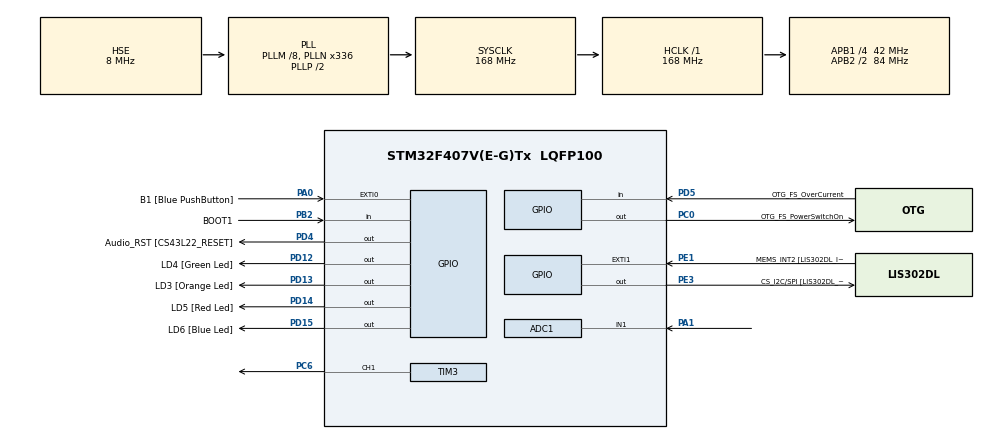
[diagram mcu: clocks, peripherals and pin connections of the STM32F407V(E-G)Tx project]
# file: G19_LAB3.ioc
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ADC1.Channel-0\#ChannelRegularConversion=ADC_CHANNEL_1
ADC1.ExternalTrigConv=ADC_EXTERNALTRIGCONV_T2_TRGO
ADC1.NbrOfConversion=1
ADC1.NbrOfConversionFlag=1
ADC1.Rank-0\#ChannelRegularConversion=1
ADC1.Resolution=ADC_RESOLUTION_8B
ADC1.SamplingTime-0\#ChannelRegularConversion=ADC_SAMPLETIME_3CYCLES
ADC1.master=1
Mcu.Family=STM32F4
Mcu.Name=STM32F407V(E-G)Tx
Mcu.Package=LQFP100
NVIC.ADC_IRQn=true\:0\:0\:false\:false\:true\:true
NVIC.PriorityGroup=NVIC_PRIORITYGROUP_0
PA0-WKUP.GPIO_Label=B1 [Blue PushButton]
PA0-WKUP.GPIO_ModeDefaultEXTI=GPIO_MODE_EVT_RISING
PA0-WKUP.GPIO_PuPd=GPIO_NOPULL
PA0-WKUP.Signal=GPXTI0
PA1.Signal=ADCx_IN1
PA10.GPIO_Label=OTG_FS_ID
PA10.GPIO_Mode=GPIO_MODE_AF_PP
PA10.GPIO_PuPd=GPIO_NOPULL
PA10.GPIO_Speed=GPIO_SPEED_FREQ_LOW
PA10.Signal=USB_OTG_FS_ID
PA11.GPIO_Label=OTG_FS_DM
PA11.GPIO_Mode=GPIO_MODE_AF_PP
PA11.GPIO_PuPd=GPIO_NOPULL
PA11.GPIO_Speed=GPIO_SPEED_FREQ_LOW
PA11.Signal=USB_OTG_FS_DM
PA12.GPIO_Label=OTG_FS_DP
PA12.GPIO_Mode=GPIO_MODE_AF_PP
PA12.GPIO_PuPd=GPIO_NOPULL
PA12.GPIO_Speed=GPIO_SPEED_FREQ_LOW
PA12.Signal=USB_OTG_FS_DP
PA13.GPIO_Label=SWDIO
PA13.Signal=SYS_JTMS-SWDIO
PA14.GPIO_Label=SWCLK
PA14.Signal=SYS_JTCK-SWCLK
PA4.GPIO_Label=I2S3_WS [CS43L22_LRCK]
PA4.GPIO_Mode=GPIO_MODE_AF_PP
PA4.GPIO_PuPd=GPIO_NOPULL
PA4.GPIO_Speed=GPIO_SPEED_FREQ_LOW
PA4.Signal=I2S3_WS
PA5.GPIO_Label=SPI1_SCK [LIS302DL_SCL/SPC]
PA5.GPIO_Mode=GPIO_MODE_AF_PP
PA5.GPIO_PuPd=GPIO_NOPULL
PA5.GPIO_Speed=GPIO_SPEED_FREQ_LOW
PA5.Signal=SPI1_SCK
PA6.GPIO_Label=SPI1_MISO [LIS302DL_SDO]
PA6.GPIO_Mode=GPIO_MODE_AF_PP
PA6.GPIO_PuPd=GPIO_NOPULL
PA6.GPIO_Speed=GPIO_SPEED_FREQ_LOW
PA6.Signal=SPI1_MISO
PA7.GPIO_Label=SPI1_MOSI [LIS302DL_SDA/SDI/SDO]
PA7.GPIO_Mode=GPIO_MODE_AF_PP
PA7.GPIO_PuPd=GPIO_NOPULL
PA7.GPIO_Speed=GPIO_SPEED_FREQ_LOW
PA7.Signal=SPI1_MOSI
PA9.GPIO_Label=VBUS_FS
PA9.GPIO_Mode=GPIO_MODE_INPUT
PA9.GPIO_PuPd=GPIO_NOPULL
PA9.Signal=USB_OTG_FS_VBUS
PB10.GPIO_Label=CLK_IN [MP45DT02_CLK]
PB10.GPIO_Mode=GPIO_MODE_AF_PP
PB10.GPIO_PuPd=GPIO_NOPULL
PB10.GPIO_Speed=GPIO_SPEED_FREQ_LOW
PB10.Signal=I2S2_CK
PB2.GPIO_Label=BOOT1
PB2.GPIO_Mode=GPIO_MODE_INPUT
PB2.GPIO_PuPd=GPIO_NOPULL
PB2.Signal=GPIO_Input
PB3.GPIO_Label=SWO
PB3.Signal=SYS_JTDO-SWO
PB6.GPIO_Label=Audio_SCL [CS43L22_SCL]
PB6.GPIO_Mode=GPIO_MODE_AF_OD
PB6.GPIO_PuPd=GPIO_NOPULL
PB6.GPIO_Speed=GPIO_SPEED_FREQ_LOW
PB6.Signal=I2C1_SCL
PB9.GPIO_Label=Audio_SDA [CS43L22_SDA]
PB9.GPIO_Mode=GPIO_MODE_AF_OD
PB9.GPIO_PuPd=GPIO_NOPULL
PB9.GPIO_Speed=GPIO_SPEED_FREQ_LOW
PB9.Signal=I2C1_SDA
PC0.GPIO_Label=OTG_FS_PowerSwitchOn
PC0.GPIO_PuPd=GPIO_NOPULL
PC0.GPIO_Speed=GPIO_SPEED_FREQ_LOW
PC0.PinState=GPIO_PIN_SET
PC0.Signal=GPIO_Output
PC10.GPIO_Label=I2S3_SCK [CS43L22_SCLK]
PC10.GPIO_Mode=GPIO_MODE_AF_PP
PC10.GPIO_PuPd=GPIO_NOPULL
PC10.GPIO_Speed=GPIO_SPEED_FREQ_LOW
PC10.Signal=I2S3_CK
PC12.GPIO_Label=I2S3_SD [CS43L22_SDIN]
PC12.GPIO_Mode=GPIO_MODE_AF_PP
PC12.GPIO_PuPd=GPIO_NOPULL
PC12.GPIO_Speed=GPIO_SPEED_FREQ_LOW
PC12.Signal=I2S3_SD
PC14-OSC32_IN.GPIO_Label=PC14-OSC32_IN
PC14-OSC32_IN.Signal=RCC_OSC32_IN
PC15-OSC32_OUT.GPIO_Label=PC15-OSC32_OUT
PC15-OSC32_OUT.Signal=RCC_OSC32_OUT
PC3.GPIO_Label=PDM_OUT [MP45DT02_DOUT]
PC3.GPIO_Mode=GPIO_MODE_AF_PP
PC3.GPIO_PuPd=GPIO_NOPULL
PC3.GPIO_Speed=GPIO_SPEED_FREQ_LOW
PC3.Signal=I2S2_SD
PC6.Signal=S_TIM3_CH1
PC7.GPIO_Label=I2S3_MCK [CS43L22_MCLK]
PC7.GPIO_Mode=GPIO_MODE_AF_PP
PC7.GPIO_PuPd=GPIO_NOPULL
PC7.GPIO_Speed=GPIO_SPEED_FREQ_LOW
PC7.Signal=I2S3_MCK
PD12.GPIO_Label=LD4 [Green Led]
PD12.GPIO_PuPd=GPIO_NOPULL
PD12.GPIO_Speed=GPIO_SPEED_FREQ_LOW
PD12.Signal=GPIO_Output
PD13.GPIO_Label=LD3 [Orange Led]
PD13.GPIO_PuPd=GPIO_NOPULL
PD13.GPIO_Speed=GPIO_SPEED_FREQ_LOW
PD13.Signal=GPIO_Output
PD14.GPIO_Label=LD5 [Red Led]
PD14.GPIO_PuPd=GPIO_NOPULL
PD14.GPIO_Speed=GPIO_SPEED_FREQ_LOW
PD14.Signal=GPIO_Output
PD15.GPIO_Label=LD6 [Blue Led]
PD15.GPIO_PuPd=GPIO_NOPULL
PD15.GPIO_Speed=GPIO_SPEED_FREQ_LOW
PD15.Signal=GPIO_Output
PD4.GPIO_Label=Audio_RST [CS43L22_RESET]
PD4.GPIO_PuPd=GPIO_NOPULL
PD4.GPIO_Speed=GPIO_SPEED_FREQ_LOW
PD4.Signal=GPIO_Output
PD5.GPIO_Label=OTG_FS_OverCurrent
PD5.GPIO_Mode=GPIO_MODE_INPUT
PD5.GPIO_PuPd=GPIO_NOPULL
PD5.Signal=GPIO_Input
PE1.GPIO_Label=MEMS_INT2 [LIS302DL_INT2]
PE1.GPIO_ModeDefaultEXTI=GPIO_MODE_EVT_RISING
PE1.GPIO_PuPd=GPIO_NOPULL
PE1.Signal=GPXTI1
PE3.GPIO_Label=CS_I2C/SPI [LIS302DL_CS_I2C/SPI]
PE3.GPIO_PuPd=GPIO_NOPULL
PE3.GPIO_Speed=GPIO_SPEED_FREQ_LOW
PE3.Signal=GPIO_Output
PH0-OSC_IN.GPIO_Label=PH0-OSC_IN
PH0-OSC_IN.Mode=HSE-External-Oscillator
PH0-OSC_IN.Signal=RCC_OSC_IN
PH1-OSC_OUT.GPIO_Label=PH1-OSC_OUT
PH1-OSC_OUT.Mode=HSE-External-Oscillator
PH1-OSC_OUT.Signal=RCC_OSC_OUT
ProjectManager.HeapSize=0x200
ProjectManager.StackSize=0x400
ProjectManager.TargetToolchain=MDK-ARM V5
RCC.48MHZClocksFreq_Value=48000000
RCC.AHBFreq_Value=168000000
RCC.APB1CLKDivider=RCC_HCLK_DIV4
RCC.APB1Freq_Value=42000000
RCC.APB1TimFreq_Value=84000000
RCC.APB2CLKDivider=RCC_HCLK_DIV2
RCC.APB2Freq_Value=84000000
RCC.APB2TimFreq_Value=168000000
RCC.CortexFreq_Value=168000000
RCC.HCLKFreq_Value=168000000
RCC.HSE_VALUE=8000000
RCC.HSI_VALUE=16000000
RCC.LSE_VALUE=32768
RCC.PLLM=8
RCC.PLLN=336
RCC.PLLQ=7
RCC.PLLSourceVirtual=RCC_PLLSOURCE_HSE
RCC.SYSCLKFreq_VALUE=168000000
RCC.SYSCLKSource=RCC_SYSCLKSOURCE_PLLCLK
RCC.VCOOutputFreq_Value=336000000
SH.ADCx_IN1.0=ADC1_IN1,IN1
SH.S_TIM3_CH1.0=TIM3_CH1,PWM Generation1 CH1
TIM2.Prescaler=10
TIM2.TIM_MasterOutputTrigger=TIM_TRGO_UPDATE
TIM3.Channel-PWM\ Generation1\ CH1=TIM_CHANNEL_1
VP_TIM2_VS_ClockSourceINT.Mode=Internal
board=STM32F4DISCOVERY

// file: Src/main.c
/**
 ******************************************************************************
 * File Name          : main.c
 * Description        : Main program body
 ******************************************************************************
 ** This notice applies to any and all portions of this file
 * that are not between comment pairs USER CODE BEGIN and
 * USER CODE END. Other portions of this file, whether
 * inserted by the user or by software development tools
 * are owned by their respective copyright owners.
 *
 * COPYRIGHT(c) 2018 STMicroelectronics
 *
 * Redistribution and use in source and binary forms, with or without modification,
 * are permitted provided that the following conditions are met:
 *   1. Redistributions of source code must retain the above copyright notice,
 *      this list of conditions and the following disclaimer.
 *   2. Redistributions in binary form must reproduce the above copyright notice,
 *      this list of conditions and the following disclaimer in the documentation
 *      and/or other materials provided with the distribution.
 *   3. Neither the name of STMicroelectronics nor the names of its contributors
 *      may be used to endorse or promote products derived from this software
 *      without specific prior written permission.
 *
 * THIS SOFTWARE IS PROVIDED BY THE COPYRIGHT HOLDERS AND CONTRIBUTORS "AS IS"
 * AND ANY EXPRESS OR IMPLIED WARRANTIES, INCLUDING, BUT NOT LIMITED TO, THE
 * IMPLIED WARRANTIES OF MERCHANTABILITY AND FITNESS FOR A PARTICULAR PURPOSE ARE
 * DISCLAIMED. IN NO EVENT SHALL THE COPYRIGHT HOLDER OR CONTRIBUTORS BE LIABLE
 * FOR ANY DIRECT, INDIRECT, INCIDENTAL, SPECIAL, EXEMPLARY, OR CONSEQUENTIAL
 * DAMAGES (INCLUDING, BUT NOT LIMITED TO, PROCUREMENT OF SUBSTITUTE GOODS OR
 * SERVICES; LOSS OF USE, DATA, OR PROFITS; OR BUSINESS INTERRUPTION) HOWEVER
 * CAUSED AND ON ANY THEORY OF LIABILITY, WHETHER IN CONTRACT, STRICT LIABILITY,
 * OR TORT (INCLUDING NEGLIGENCE OR OTHERWISE) ARISING IN ANY WAY OUT OF THE USE
 * OF THIS SOFTWARE, EVEN IF ADVISED OF THE POSSIBILITY OF SUCH DAMAGE.
 *
 ******************************************************************************
 */
#include "main.h"
#include "stm32f4xx_hal.h"
#include "voltmeter.h"

#define STAR 11
#define HASH 12
#define SYSTICK_FREQUENCY 1000
#define ADC_RES 8

void write_to_display(float val);
void shut_off_display(void);

ADC_HandleTypeDef hadc1;

TIM_HandleTypeDef htim2;
TIM_HandleTypeDef htim3;

int counter = 0;
int systick_counter = 0;
int pmode = 0;
int target = 1;
int reading = -1;
float temp_voltage = 0.0;
float target_voltage = 1.0;
int state_counter = 0;
float the_reading = 0.0;
float filtered_val;

float duty_cycle = 0.5;

int state = FIRST_KEY;
int col = 0;

/* USER CODE BEGIN PV */
/* Private variables ---------------------------------------------------------*/

/* USER CODE END PV */

void SystemClock_Config(void);
static void MX_GPIO_Init(void);
static void MX_ADC1_Init(void);
static void MX_TIM2_Init(void);
static void MX_TIM3_Init(void);

void HAL_TIM_MspPostInit(TIM_HandleTypeDef *htim);

float duty_cycles[] = {0.25, 0.5, 0.75, 1.0};

/* USER CODE BEGIN PFP */
/* Private function prototypes -----------------------------------------------*/

/* USER CODE END PFP */

// for storing adc value
uint8_t adc_value;

int holding = 0;
int hold_count = 0;

int main(void)
{
	int last_mode = 0;
	int last_state = -1;
	HAL_Init();
	SystemClock_Config();

	MX_GPIO_Init();
	MX_ADC1_Init();
	MX_TIM2_Init();
	MX_TIM3_Init();

	HAL_GPIO_WritePin(GPIOD, LD6_Pin, GPIO_PIN_SET);
	HAL_TIM_PWM_Start(&htim3, TIM_CHANNEL_1);

	// Start TIM2 Timer
	HAL_TIM_Base_Start(&htim2);
	// Start ADC
	HAL_ADC_Start_IT(&hadc1);
	/* USER CODE END 2 */

	/* Infinite loop */
//	int keypad_matrix[3][4] = {1,4,7,STAR,2,5,8,0,3,6,9,HASH};
	int keypad_matrix[3][4];
	keypad_matrix[0][0] = 1;
	keypad_matrix[0][1] = 4;
	keypad_matrix[0][2] = 7;
	keypad_matrix[0][3] = STAR;
	keypad_matrix[1][0] = 2;
	keypad_matrix[1][1] = 5;
	keypad_matrix[1][2] = 8;
	keypad_matrix[1][3] = 0;
	keypad_matrix[2][0] = 3;
	keypad_matrix[2][1] = 6;
	keypad_matrix[2][2] = 9;
	keypad_matrix[2][3] = HASH;
	int target = 1; //For keypad debugging

	int last_col = -1;

	while (1)
	{
		//col = 0;
		reading = -1;
		counter = 0;
		/*
		 * Remove while loop
		 * int read_keypad = 0
		 * change if(col != last_col) to if(!(read_keypad || col == last_col))
		 * when reading >= 0 read_keypad = 1
		 * change if(state_counter != last_state) to if(read_keypad == 1 && state_counter != last_state)
		 * immediately under (if state_counter != last_state && read_keypad == 1) set read_keypad = 0
		 */
		while(counter <= 350) {
			if(col != last_col) {
				last_col = col;
			//for(col = 0; col < 3; col++) {
				//col = (col + 1) % 3;
				switch(col) {
					case 0:
						HAL_GPIO_WritePin(KEY_C1, GPIO_PIN_SET);
						HAL_GPIO_WritePin(KEY_C2, GPIO_PIN_RESET);
						HAL_GPIO_WritePin(KEY_C3, GPIO_PIN_RESET);
						break;
					case 1:
						HAL_GPIO_WritePin(KEY_C1, GPIO_PIN_RESET);
						HAL_GPIO_WritePin(KEY_C2, GPIO_PIN_SET);
						HAL_GPIO_WritePin(KEY_C3, GPIO_PIN_RESET);
						break;
					case 2:
						HAL_GPIO_WritePin(KEY_C1, GPIO_PIN_RESET);
						HAL_GPIO_WritePin(KEY_C2, GPIO_PIN_RESET);
						HAL_GPIO_WritePin(KEY_C3, GPIO_PIN_SET);
						break;
					default:
						break;
				}
			}
			if(GPIOB->IDR & GPIO_PIN_8) reading = keypad_matrix[last_col][0];
			else if(GPIOB->IDR & GPIO_PIN_7) reading = keypad_matrix[last_col][1];
			else if(GPIOB->IDR & GPIO_PIN_5) reading = keypad_matrix[last_col][2];
			else if (GPIOD->IDR & GPIO_PIN_7) reading = keypad_matrix[last_col][3];
			if(reading >= 0) break;
		}
		if (state_counter != last_state) {
			last_state = state_counter;
			switch(state) {
				case FIRST_KEY:
					temp_voltage = 0.0;
					if(reading < 3 && reading >= 0) {
						temp_voltage = (float) reading;
						state = SECOND_KEY;
						holding = 0;
						hold_count = 0;
					} else if(reading == STAR) {
						holding = 1;
						if(hold_count > 3 * SYSTICK_FREQUENCY) {
							state = SLEEP;
						} else if(hold_count > 1 * SYSTICK_FREQUENCY) {
							state = FIRST_KEY;
							target_voltage = 0.0;
						}
					} else {
						holding = 0;
						hold_count = 0;
					}
					break;
				case SECOND_KEY:
					if(reading == STAR) {
						holding = 1;
						if(hold_count > 3 * SYSTICK_FREQUENCY) {
							state = SLEEP;
						} else if(hold_count > 1 * SYSTICK_FREQUENCY) {
							state = FIRST_KEY;
							target_voltage = 0.0;
						} else {
							state = FIRST_KEY;
						}
					} else {
						holding = 0;
						hold_count = 0;
						if(reading < 10 && reading >= 0) {
							temp_voltage += (float) reading / 10.0;
							state = WAIT;
						} else if(reading == HASH) {
							state = FIRST_KEY;
							target_voltage = temp_voltage;
						}
					}
					break;
				case WAIT:
					if(reading == STAR) {
						holding = 1;
						if(hold_count > 3 * SYSTICK_FREQUENCY) {
							state = SLEEP;
						} else if(hold_count > 1 * SYSTICK_FREQUENCY) {
							state = FIRST_KEY;
							target_voltage = 0.0;
						} else {
							state = SECOND_KEY;
							temp_voltage = (float)((int) temp_voltage);
						}
					} else if(reading == HASH) {
						state = FIRST_KEY;
						target_voltage = temp_voltage;
					}
					break;
				case SLEEP:
					target_voltage = 0.0;
					if(reading == HASH) {
						holding = 1;
						if(hold_count >= 3 * SYSTICK_FREQUENCY) {
							state = FIRST_KEY;
							holding = 0;
							hold_count = 0;
						}
					} else {
						holding = 0;
						hold_count = 0;
					}
					break;
			}
		}
		switch(state) {
			case FIRST_KEY:
				HAL_GPIO_WritePin(GPIOD, LD6_Pin, GPIO_PIN_SET);
				HAL_GPIO_WritePin(GPIOD, LD4_Pin, GPIO_PIN_RESET);
				HAL_GPIO_WritePin(GPIOD, LD3_Pin, GPIO_PIN_RESET);
				HAL_GPIO_WritePin(GPIOD, LD5_Pin, GPIO_PIN_RESET);
				break;
			case SECOND_KEY:
				HAL_GPIO_WritePin(GPIOD, LD6_Pin, GPIO_PIN_RESET);
				HAL_GPIO_WritePin(GPIOD, LD4_Pin, GPIO_PIN_SET);
				HAL_GPIO_WritePin(GPIOD, LD3_Pin, GPIO_PIN_RESET);
				HAL_GPIO_WritePin(GPIOD, LD5_Pin, GPIO_PIN_RESET);
				break;
			case WAIT:
				HAL_GPIO_WritePin(GPIOD, LD6_Pin, GPIO_PIN_RESET);
				HAL_GPIO_WritePin(GPIOD, LD4_Pin, GPIO_PIN_RESET);
				HAL_GPIO_WritePin(GPIOD, LD3_Pin, GPIO_PIN_SET);
				HAL_GPIO_WritePin(GPIOD, LD5_Pin, GPIO_PIN_RESET);
				break;
			default:
				HAL_GPIO_WritePin(GPIOD, LD6_Pin, GPIO_PIN_RESET);
				HAL_GPIO_WritePin(GPIOD, LD4_Pin, GPIO_PIN_RESET);
				HAL_GPIO_WritePin(GPIOD, LD3_Pin, GPIO_PIN_RESET);
				HAL_GPIO_WritePin(GPIOD, LD5_Pin, GPIO_PIN_SET);
				break;
		}
//		}
//		last_mode = counter;
	}

}

/** System Clock Configuration
*/
void SystemClock_Config(void)
{

	RCC_OscInitTypeDef RCC_OscInitStruct;
	RCC_ClkInitTypeDef RCC_ClkInitStruct;

	/**Configure the main internal regulator output voltage
	*/
	__HAL_RCC_PWR_CLK_ENABLE();

	__HAL_PWR_VOLTAGESCALING_CONFIG(PWR_REGULATOR_VOLTAGE_SCALE1);

	/**Initializes the CPU, AHB and APB busses clocks
	*/
	RCC_OscInitStruct.OscillatorType = RCC_OSCILLATORTYPE_HSE;
	RCC_OscInitStruct.HSEState = RCC_HSE_ON;
	RCC_OscInitStruct.PLL.PLLState = RCC_PLL_ON;
	RCC_OscInitStruct.PLL.PLLSource = RCC_PLLSOURCE_HSE;
	RCC_OscInitStruct.PLL.PLLM = 8;
	RCC_OscInitStruct.PLL.PLLN = 336;
	RCC_OscInitStruct.PLL.PLLP = RCC_PLLP_DIV2;
	RCC_OscInitStruct.PLL.PLLQ = 7;
	if (HAL_RCC_OscConfig(&RCC_OscInitStruct) != HAL_OK)
	{
		_Error_Handler(__FILE__, __LINE__);
	}

	/**Initializes the CPU, AHB and APB busses clocks
	*/
	RCC_ClkInitStruct.ClockType = RCC_CLOCKTYPE_HCLK|RCC_CLOCKTYPE_SYSCLK
		|RCC_CLOCKTYPE_PCLK1|RCC_CLOCKTYPE_PCLK2;
	RCC_ClkInitStruct.SYSCLKSource = RCC_SYSCLKSOURCE_PLLCLK;
	RCC_ClkInitStruct.AHBCLKDivider = RCC_SYSCLK_DIV1;
	RCC_ClkInitStruct.APB1CLKDivider = RCC_HCLK_DIV4;
	RCC_ClkInitStruct.APB2CLKDivider = RCC_HCLK_DIV2;

	if (HAL_RCC_ClockConfig(&RCC_ClkInitStruct, FLASH_LATENCY_5) != HAL_OK)
	{
		_Error_Handler(__FILE__, __LINE__);
	}

	/**Configure the Systick interrupt time
	*/
	HAL_SYSTICK_Config(HAL_RCC_GetHCLKFreq()/SYSTICK_FREQUENCY);

	/**Configure the Systick
	*/
	HAL_SYSTICK_CLKSourceConfig(SYSTICK_CLKSOURCE_HCLK);

	/* SysTick_IRQn interrupt configuration */
	HAL_NVIC_SetPriority(SysTick_IRQn, 0, 0);
}

/* ADC1 init function */
static void MX_ADC1_Init(void)
{

	ADC_ChannelConfTypeDef sConfig;

	/**Configure the global features of the ADC (Clock, Resolution, Data Alignment and number of conversion)
	*/
	hadc1.Instance = ADC1;
	hadc1.Init.ClockPrescaler = ADC_CLOCK_SYNC_PCLK_DIV4;
	hadc1.Init.Resolution = ADC_RESOLUTION_8B;
	hadc1.Init.ScanConvMode = DISABLE;
	hadc1.Init.ContinuousConvMode = DISABLE;
	hadc1.Init.DiscontinuousConvMode = DISABLE;
	hadc1.Init.ExternalTrigConvEdge = ADC_EXTERNALTRIGCONVEDGE_RISING;
	hadc1.Init.ExternalTrigConv = ADC_EXTERNALTRIGCONV_T2_TRGO;
	hadc1.Init.DataAlign = ADC_DATAALIGN_RIGHT;
	hadc1.Init.NbrOfConversion = 1;
	hadc1.Init.DMAContinuousRequests = DISABLE;
	hadc1.Init.EOCSelection = ADC_EOC_SINGLE_CONV;
	if (HAL_ADC_Init(&hadc1) != HAL_OK)
	{
		_Error_Handler(__FILE__, __LINE__);
	}

	/**Configure for the selected ADC regular channel its corresponding rank in the sequencer and its sample time.
	*/
	sConfig.Channel = ADC_CHANNEL_1;
	sConfig.Rank = 1;
	sConfig.SamplingTime = ADC_SAMPLETIME_28CYCLES; // changed from 3 to 28 cycles, read more into why
	if (HAL_ADC_ConfigChannel(&hadc1, &sConfig) != HAL_OK)
	{
		_Error_Handler(__FILE__, __LINE__);
	}

}

/* TIM2 init function */
static void MX_TIM2_Init(void)
{

	TIM_ClockConfigTypeDef sClockSourceConfig;
	TIM_MasterConfigTypeDef sMasterConfig;

	htim2.Instance = TIM2;
	htim2.Init.Prescaler = 83999; // changed from 10 to 84000 so that sampling frequency is 1KHz
	htim2.Init.CounterMode = TIM_COUNTERMODE_UP;
	htim2.Init.Period = 1; // this activates the ADC in 1 period (ms)
	htim2.Init.ClockDivision = TIM_CLOCKDIVISION_DIV1;
	if (HAL_TIM_Base_Init(&htim2) != HAL_OK)
	{
		_Error_Handler(__FILE__, __LINE__);
	}

	sClockSourceConfig.ClockSource = TIM_CLOCKSOURCE_INTERNAL;
	if (HAL_TIM_ConfigClockSource(&htim2, &sClockSourceConfig) != HAL_OK)
	{
		_Error_Handler(__FILE__, __LINE__);
	}

	sMasterConfig.MasterOutputTrigger = TIM_TRGO_UPDATE;
	sMasterConfig.MasterSlaveMode = TIM_MASTERSLAVEMODE_DISABLE;
	if (HAL_TIMEx_MasterConfigSynchronization(&htim2, &sMasterConfig) != HAL_OK)
	{
		_Error_Handler(__FILE__, __LINE__);
	}

}

/* TIM3 init function */
static void MX_TIM3_Init(void)
{

	TIM_MasterConfigTypeDef sMasterConfig;
	TIM_OC_InitTypeDef sConfigOC;

	htim3.Instance = TIM3;
	htim3.Init.Prescaler = 0;
	htim3.Init.CounterMode = TIM_COUNTERMODE_UP;
	htim3.Init.Period = PWM_PERIOD;
	htim3.Init.ClockDivision = TIM_CLOCKDIVISION_DIV1;
	if (HAL_TIM_PWM_Init(&htim3) != HAL_OK)
	{
		_Error_Handler(__FILE__, __LINE__);
	}

	sMasterConfig.MasterOutputTrigger = TIM_TRGO_RESET;
	sMasterConfig.MasterSlaveMode = TIM_MASTERSLAVEMODE_DISABLE;
	if (HAL_TIMEx_MasterConfigSynchronization(&htim3, &sMasterConfig) != HAL_OK)
	{
		_Error_Handler(__FILE__, __LINE__);
	}

	sConfigOC.OCMode = TIM_OCMODE_PWM1;
	sConfigOC.Pulse = duty_cycle * PWM_PERIOD;
	sConfigOC.OCPolarity = TIM_OCPOLARITY_HIGH;
	sConfigOC.OCFastMode = TIM_OCFAST_DISABLE;
	if (HAL_TIM_PWM_ConfigChannel(&htim3, &sConfigOC, TIM_CHANNEL_1) != HAL_OK)
	{
		_Error_Handler(__FILE__, __LINE__);
	}

	HAL_TIM_MspPostInit(&htim3);
}

/** Configure pins as
 * Analog
 * Input
 * Output
 * EVENT_OUT
 * EXTI
 PC3   ------> I2S2_SD
 PA4   ------> I2S3_WS
 PA5   ------> SPI1_SCK
 PA6   ------> SPI1_MISO
 PA7   ------> SPI1_MOSI
 PB10   ------> I2S2_CK
 PC7   ------> I2S3_MCK
 PA9   ------> USB_OTG_FS_VBUS
 PA10   ------> USB_OTG_FS_ID
 PA11   ------> USB_OTG_FS_DM
 PA12   ------> USB_OTG_FS_DP
 PC10   ------> I2S3_CK
 PC12   ------> I2S3_SD
 PB6   ------> I2C1_SCL
 PB9   ------> I2C1_SDA
 */
static void MX_GPIO_Init(void)
{

	GPIO_InitTypeDef GPIO_InitStruct;

	/* GPIO Ports Clock Enable */
	__HAL_RCC_GPIOE_CLK_ENABLE();
	__HAL_RCC_GPIOC_CLK_ENABLE();
	__HAL_RCC_GPIOH_CLK_ENABLE();
	__HAL_RCC_GPIOA_CLK_ENABLE();
	__HAL_RCC_GPIOB_CLK_ENABLE();
	__HAL_RCC_GPIOD_CLK_ENABLE();

	/*Configure GPIO pin Output Level */
	HAL_GPIO_WritePin(CS_I2C_SPI_GPIO_Port, CS_I2C_SPI_Pin, GPIO_PIN_RESET);

	/*Configure GPIO pin Output Level */
	HAL_GPIO_WritePin(OTG_FS_PowerSwitchOn_GPIO_Port, OTG_FS_PowerSwitchOn_Pin, GPIO_PIN_SET);

	/*Configure GPIO pin Output Level */
	HAL_GPIO_WritePin(GPIOD, LD4_Pin|LD3_Pin|LD5_Pin|LD6_Pin
			|Audio_RST_Pin, GPIO_PIN_RESET);

	/*Configure GPIO pin : CS_I2C_SPI_Pin */
	GPIO_InitStruct.Pin = CS_I2C_SPI_Pin;
	GPIO_InitStruct.Mode = GPIO_MODE_OUTPUT_PP;
	GPIO_InitStruct.Pull = GPIO_NOPULL;
	GPIO_InitStruct.Speed = GPIO_SPEED_FREQ_LOW;
	HAL_GPIO_Init(CS_I2C_SPI_GPIO_Port, &GPIO_InitStruct);

	/*Configure GPIO pin : OTG_FS_PowerSwitchOn_Pin */
	GPIO_InitStruct.Pin = OTG_FS_PowerSwitchOn_Pin;
	GPIO_InitStruct.Mode = GPIO_MODE_OUTPUT_PP;
	GPIO_InitStruct.Pull = GPIO_NOPULL;
	GPIO_InitStruct.Speed = GPIO_SPEED_FREQ_LOW;
	HAL_GPIO_Init(OTG_FS_PowerSwitchOn_GPIO_Port, &GPIO_InitStruct);

	/*Configure GPIO pin : PDM_OUT_Pin */
	GPIO_InitStruct.Pin = PDM_OUT_Pin;
	GPIO_InitStruct.Mode = GPIO_MODE_AF_PP;
	GPIO_InitStruct.Pull = GPIO_NOPULL;
	GPIO_InitStruct.Speed = GPIO_SPEED_FREQ_LOW;
	GPIO_InitStruct.Alternate = GPIO_AF5_SPI2;
	HAL_GPIO_Init(PDM_OUT_GPIO_Port, &GPIO_InitStruct);

	/*Configure GPIO pin : B1_Pin */
	GPIO_InitStruct.Pin = B1_Pin;
	GPIO_InitStruct.Mode = GPIO_MODE_EVT_RISING;
	GPIO_InitStruct.Pull = GPIO_NOPULL;
	HAL_GPIO_Init(B1_GPIO_Port, &GPIO_InitStruct);

	/*Configure GPIO pin : I2S3_WS_Pin */
	GPIO_InitStruct.Pin = I2S3_WS_Pin;
	GPIO_InitStruct.Mode = GPIO_MODE_AF_PP;
	GPIO_InitStruct.Pull = GPIO_NOPULL;
	GPIO_InitStruct.Speed = GPIO_SPEED_FREQ_LOW;
	GPIO_InitStruct.Alternate = GPIO_AF6_SPI3;
	HAL_GPIO_Init(I2S3_WS_GPIO_Port, &GPIO_InitStruct);

	/*Configure GPIO pins : SPI1_SCK_Pin SPI1_MISO_Pin SPI1_MOSI_Pin */
	GPIO_InitStruct.Pin = SPI1_SCK_Pin|SPI1_MISO_Pin|SPI1_MOSI_Pin;
	GPIO_InitStruct.Mode = GPIO_MODE_AF_PP;
	GPIO_InitStruct.Pull = GPIO_NOPULL;
	GPIO_InitStruct.Speed = GPIO_SPEED_FREQ_LOW;
	GPIO_InitStruct.Alternate = GPIO_AF5_SPI1;
	HAL_GPIO_Init(GPIOA, &GPIO_InitStruct);

	/*Configure GPIO pin : BOOT1_Pin */
	GPIO_InitStruct.Pin = BOOT1_Pin;
	GPIO_InitStruct.Mode = GPIO_MODE_INPUT;
	GPIO_InitStruct.Pull = GPIO_NOPULL;
	HAL_GPIO_Init(BOOT1_GPIO_Port, &GPIO_InitStruct);

	/*Configure GPIO pin : CLK_IN_Pin */
	GPIO_InitStruct.Pin = CLK_IN_Pin;
	GPIO_InitStruct.Mode = GPIO_MODE_AF_PP;
	GPIO_InitStruct.Pull = GPIO_NOPULL;
	GPIO_InitStruct.Speed = GPIO_SPEED_FREQ_LOW;
	GPIO_InitStruct.Alternate = GPIO_AF5_SPI2;
	HAL_GPIO_Init(CLK_IN_GPIO_Port, &GPIO_InitStruct);

	/*Configure GPIO pins : LD4_Pin LD3_Pin LD5_Pin LD6_Pin
	  Audio_RST_Pin */
	GPIO_InitStruct.Pin = LD4_Pin|LD3_Pin|LD5_Pin|LD6_Pin
		|Audio_RST_Pin;
	GPIO_InitStruct.Mode = GPIO_MODE_OUTPUT_PP;
	GPIO_InitStruct.Pull = GPIO_NOPULL;
	GPIO_InitStruct.Speed = GPIO_SPEED_FREQ_LOW;
	HAL_GPIO_Init(GPIOD, &GPIO_InitStruct);

	/*Configure GPIO pins : I2S3_MCK_Pin I2S3_SCK_Pin I2S3_SD_Pin */
	GPIO_InitStruct.Pin = I2S3_MCK_Pin|I2S3_SCK_Pin|I2S3_SD_Pin;
	GPIO_InitStruct.Mode = GPIO_MODE_AF_PP;
	GPIO_InitStruct.Pull = GPIO_NOPULL;
	GPIO_InitStruct.Speed = GPIO_SPEED_FREQ_LOW;
	GPIO_InitStruct.Alternate = GPIO_AF6_SPI3;
	HAL_GPIO_Init(GPIOC, &GPIO_InitStruct);

	/*Configure GPIO pin : VBUS_FS_Pin */
	GPIO_InitStruct.Pin = VBUS_FS_Pin;
	GPIO_InitStruct.Mode = GPIO_MODE_INPUT;
	GPIO_InitStruct.Pull = GPIO_NOPULL;
	HAL_GPIO_Init(VBUS_FS_GPIO_Port, &GPIO_InitStruct);

	/*Configure GPIO pins : OTG_FS_ID_Pin OTG_FS_DM_Pin OTG_FS_DP_Pin */
	GPIO_InitStruct.Pin = OTG_FS_ID_Pin|OTG_FS_DM_Pin|OTG_FS_DP_Pin;
	GPIO_InitStruct.Mode = GPIO_MODE_AF_PP;
	GPIO_InitStruct.Pull = GPIO_NOPULL;
	GPIO_InitStruct.Speed = GPIO_SPEED_FREQ_LOW;
	GPIO_InitStruct.Alternate = GPIO_AF10_OTG_FS;
	HAL_GPIO_Init(GPIOA, &GPIO_InitStruct);

	/*Configure GPIO pin : OTG_FS_OverCurrent_Pin */
	GPIO_InitStruct.Pin = OTG_FS_OverCurrent_Pin;
	GPIO_InitStruct.Mode = GPIO_MODE_INPUT;
	GPIO_InitStruct.Pull = GPIO_NOPULL;
	HAL_GPIO_Init(OTG_FS_OverCurrent_GPIO_Port, &GPIO_InitStruct);

	/*Configure GPIO pins : Audio_SCL_Pin Audio_SDA_Pin */
	GPIO_InitStruct.Pin = Audio_SCL_Pin|Audio_SDA_Pin;
	GPIO_InitStruct.Mode = GPIO_MODE_AF_OD;
	GPIO_InitStruct.Pull = GPIO_PULLUP;
	GPIO_InitStruct.Speed = GPIO_SPEED_FREQ_LOW;
	GPIO_InitStruct.Alternate = GPIO_AF4_I2C1;
	HAL_GPIO_Init(GPIOB, &GPIO_InitStruct);

	/*Configure GPIO pin : MEMS_INT2_Pin */
	GPIO_InitStruct.Pin = MEMS_INT2_Pin;
	GPIO_InitStruct.Mode = GPIO_MODE_EVT_RISING;
	GPIO_InitStruct.Pull = GPIO_NOPULL;
	HAL_GPIO_Init(MEMS_INT2_GPIO_Port, &GPIO_InitStruct);

	/*Configure 7 segment pins*/
	GPIO_InitStruct.Pin = GPIO_PIN_7|GPIO_PIN_11|GPIO_PIN_10|GPIO_PIN_14|GPIO_PIN_15;
	GPIO_InitStruct.Mode = GPIO_MODE_OUTPUT_PP;
	GPIO_InitStruct.Pull = GPIO_NOPULL;
	GPIO_InitStruct.Speed = GPIO_SPEED_FREQ_LOW;
	HAL_GPIO_Init(GPIOE, &GPIO_InitStruct);
	GPIO_InitStruct.Pin = GPIO_PIN_12|GPIO_PIN_13;
	GPIO_InitStruct.Mode = GPIO_MODE_OUTPUT_PP;
	GPIO_InitStruct.Pull = GPIO_NOPULL;
	GPIO_InitStruct.Speed = GPIO_SPEED_FREQ_LOW;
	HAL_GPIO_Init(GPIOB, &GPIO_InitStruct);
	GPIO_InitStruct.Pin = GPIO_PIN_8;
	GPIO_InitStruct.Mode = GPIO_MODE_OUTPUT_PP;
	GPIO_InitStruct.Pull = GPIO_NOPULL;
	GPIO_InitStruct.Speed = GPIO_SPEED_FREQ_LOW;
	HAL_GPIO_Init(GPIOD, &GPIO_InitStruct);

	/*Configure digit selector pins*/
	GPIO_InitStruct.Pin = GPIO_PIN_2|GPIO_PIN_3|GPIO_PIN_0;
	GPIO_InitStruct.Mode = GPIO_MODE_OUTPUT_PP;
	GPIO_InitStruct.Pull = GPIO_NOPULL;
	GPIO_InitStruct.Speed = GPIO_SPEED_FREQ_LOW;
	HAL_GPIO_Init(GPIOD, &GPIO_InitStruct);

	/*Configure keypad column pins*/
	GPIO_InitStruct.Pin = GPIO_PIN_5|GPIO_PIN_3|GPIO_PIN_1;
	GPIO_InitStruct.Mode = GPIO_MODE_OUTPUT_PP;
	GPIO_InitStruct.Pull = GPIO_NOPULL;
	GPIO_InitStruct.Speed = GPIO_SPEED_FREQ_LOW;
	HAL_GPIO_Init(GPIOE, &GPIO_InitStruct);

	/*Configure keypad row pins*/
	GPIO_InitStruct.Pin = GPIO_PIN_8|GPIO_PIN_7|GPIO_PIN_5;
	GPIO_InitStruct.Mode = GPIO_MODE_INPUT;
	GPIO_InitStruct.Pull = GPIO_PULLDOWN;
	HAL_GPIO_Init(GPIOB, &GPIO_InitStruct);
	GPIO_InitStruct.Pin = GPIO_PIN_7;
	GPIO_InitStruct.Mode = GPIO_MODE_INPUT;
	GPIO_InitStruct.Pull = GPIO_PULLDOWN;
	HAL_GPIO_Init(GPIOD, &GPIO_InitStruct);

	/*Configure GPIO pin : PA0 */
	GPIO_InitStruct.Pin = GPIO_PIN_0;
	GPIO_InitStruct.Mode = GPIO_MODE_IT_RISING;
	GPIO_InitStruct.Pull = GPIO_NOPULL;
	HAL_GPIO_Init(GPIOA, &GPIO_InitStruct);

	HAL_NVIC_SetPriority(EXTI0_IRQn, 0, 0);
	HAL_NVIC_EnableIRQ(EXTI0_IRQn);
}

/* USER CODE BEGIN 4 */
// ADC Conversion Function. This function is called whenever the ADC is activated!
void HAL_ADC_ConvCpltCallback(ADC_HandleTypeDef* hadc)
{
  /* Prevent unused argument(s) compilation warning */
	UNUSED(hadc);
	adc_value = HAL_ADC_GetValue(&hadc1);
	//float filtered_val;
	FIR_C(adc_value, &filtered_val);
	float voltage_reading = 3.0 * filtered_val / ((1 << ADC_RES) - 1.0);
	plot_point(voltage_reading, &the_reading);
	adjust_pwm(voltage_reading, target_voltage);
}
/* USER CODE END 4 */

void _Error_Handler(char * file, int line)
{
	while(1)
	{
	}
}

/************************ (C) COPYRIGHT STMicroelectronics *****END OF FILE****/
